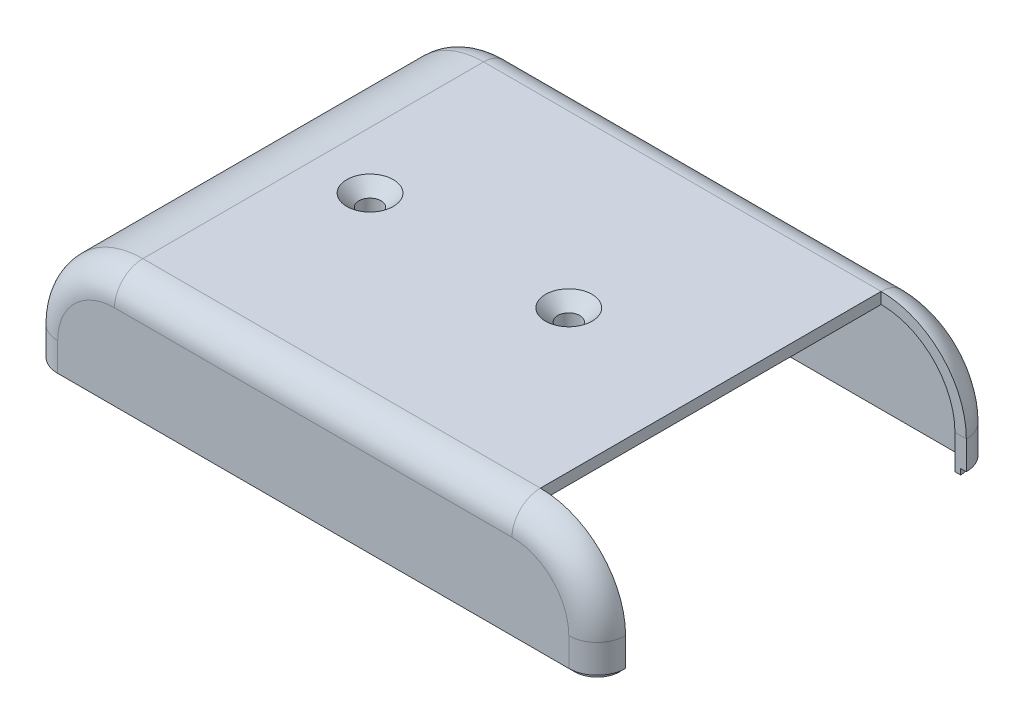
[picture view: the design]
ISO-10303-21;
HEADER;
FILE_DESCRIPTION(('STEP AP214'),'2;1');
FILE_NAME('part.step','',(''),(''),'','','');
FILE_SCHEMA(('AUTOMOTIVE_DESIGN { 1 0 10303 214 1 1 1 1 }'));
ENDSEC;
DATA;
#1=APPLICATION_CONTEXT('core data for automotive mechanical design processes');
#2=APPLICATION_PROTOCOL_DEFINITION('international standard','automotive_design',2000,#1);
#3=PRODUCT_CONTEXT('',#1,'mechanical');
#4=PRODUCT('Part','Part','',(#3));
#5=PRODUCT_RELATED_PRODUCT_CATEGORY('part','',(#4));
#6=PRODUCT_DEFINITION_FORMATION('','',#4);
#7=PRODUCT_DEFINITION_CONTEXT('part definition',#1,'design');
#8=PRODUCT_DEFINITION('design','',#6,#7);
#9=PRODUCT_DEFINITION_SHAPE('','',#8);
#10=(LENGTH_UNIT() NAMED_UNIT(*) SI_UNIT(.MILLI.,.METRE.));
#11=(NAMED_UNIT(*) PLANE_ANGLE_UNIT() SI_UNIT($,.RADIAN.));
#12=(NAMED_UNIT(*) SI_UNIT($,.STERADIAN.) SOLID_ANGLE_UNIT());
#13=UNCERTAINTY_MEASURE_WITH_UNIT(LENGTH_MEASURE(1.E-05),#10,'distance_accuracy_value','');
#14=(GEOMETRIC_REPRESENTATION_CONTEXT(3) GLOBAL_UNCERTAINTY_ASSIGNED_CONTEXT((#13)) GLOBAL_UNIT_ASSIGNED_CONTEXT((#10,
#11,#12)) REPRESENTATION_CONTEXT('',''));
#15=CARTESIAN_POINT('',(0.,0.,0.));
#16=DIRECTION('',(0.,0.,1.));
#17=DIRECTION('',(1.,0.,0.));
#18=AXIS2_PLACEMENT_3D('',#15,#16,#17);
#19=CARTESIAN_POINT('',(50.,18.,-35.));
#20=DIRECTION('',(0.,-1.,0.));
#21=DIRECTION('',(0.,0.,-1.));
#22=AXIS2_PLACEMENT_3D('',#19,#20,#21);
#23=PLANE('',#22);
#24=CARTESIAN_POINT('',(9.99999999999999,18.,0.));
#25=DIRECTION('',(0.,-1.,0.));
#26=DIRECTION('',(0.,0.,-1.));
#27=AXIS2_PLACEMENT_3D('',#24,#25,#26);
#28=CIRCLE('',#27,5.05368379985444);
#29=CARTESIAN_POINT('',(9.99999999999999,18.,-5.05368379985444));
#30=VERTEX_POINT('',#29);
#31=EDGE_CURVE('E44',#30,#30,#28,.F.);
#32=ORIENTED_EDGE('',*,*,#31,.T.);
#33=EDGE_LOOP('',(#32));
#34=FACE_BOUND('',#33,.T.);
#35=CARTESIAN_POINT('',(-25.,18.,0.));
#36=DIRECTION('',(0.,-1.,0.));
#37=DIRECTION('',(0.,0.,-1.));
#38=AXIS2_PLACEMENT_3D('',#35,#36,#37);
#39=CIRCLE('',#38,5.05368379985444);
#40=CARTESIAN_POINT('',(-25.,18.,-5.05368379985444));
#41=VERTEX_POINT('',#40);
#42=EDGE_CURVE('E550',#41,#41,#39,.F.);
#43=ORIENTED_EDGE('',*,*,#42,.T.);
#44=EDGE_LOOP('',(#43));
#45=FACE_BOUND('',#44,.T.);
#46=DIRECTION('',(0.,0.,1.));
#47=VECTOR('',#46,1.);
#48=CARTESIAN_POINT('',(35.,18.,-35.));
#49=LINE('',#48,#47);
#50=CARTESIAN_POINT('',(35.,18.,30.));
#51=VERTEX_POINT('',#50);
#52=CARTESIAN_POINT('',(35.,18.,-30.));
#53=VERTEX_POINT('',#52);
#54=EDGE_CURVE('E435',#51,#53,#49,.F.);
#55=ORIENTED_EDGE('',*,*,#54,.F.);
#56=DIRECTION('',(1.,0.,0.));
#57=VECTOR('',#56,1.);
#58=CARTESIAN_POINT('',(50.,18.,30.));
#59=LINE('',#58,#57);
#60=CARTESIAN_POINT('',(-35.,18.,30.));
#61=VERTEX_POINT('',#60);
#62=EDGE_CURVE('E400',#61,#51,#59,.T.);
#63=ORIENTED_EDGE('',*,*,#62,.F.);
#64=DIRECTION('',(0.,0.,-1.));
#65=VECTOR('',#64,1.);
#66=CARTESIAN_POINT('',(-35.,18.,-35.));
#67=LINE('',#66,#65);
#68=CARTESIAN_POINT('',(-35.,18.,-30.));
#69=VERTEX_POINT('',#68);
#70=EDGE_CURVE('E387',#69,#61,#67,.F.);
#71=ORIENTED_EDGE('',*,*,#70,.F.);
#72=DIRECTION('',(1.,0.,0.));
#73=VECTOR('',#72,1.);
#74=CARTESIAN_POINT('',(50.,18.,-30.));
#75=LINE('',#74,#73);
#76=EDGE_CURVE('E398',#53,#69,#75,.F.);
#77=ORIENTED_EDGE('',*,*,#76,.F.);
#78=EDGE_LOOP('',(#55,#63,#71,#77));
#79=FACE_BOUND('',#78,.T.);
#80=ADVANCED_FACE('F34',(#34,#45,#79),#23,.T.);
#81=CARTESIAN_POINT('',(-50.,20.,-35.));
#82=DIRECTION('',(0.,0.,1.));
#83=DIRECTION('',(1.,0.,0.));
#84=AXIS2_PLACEMENT_3D('',#81,#82,#83);
#85=PLANE('',#84);
#86=CARTESIAN_POINT('',(35.,5.,-35.));
#87=DIRECTION('',(0.,0.,1.));
#88=DIRECTION('',(1.,0.,0.));
#89=AXIS2_PLACEMENT_3D('',#86,#87,#88);
#90=CIRCLE('',#89,10.);
#91=CARTESIAN_POINT('',(35.,15.,-35.));
#92=VERTEX_POINT('',#91);
#93=CARTESIAN_POINT('',(45.,5.,-35.));
#94=VERTEX_POINT('',#93);
#95=EDGE_CURVE('E473',#92,#94,#90,.F.);
#96=ORIENTED_EDGE('',*,*,#95,.T.);
#97=DIRECTION('',(0.,-1.,0.));
#98=VECTOR('',#97,1.);
#99=CARTESIAN_POINT('',(45.,20.,-35.));
#100=LINE('',#99,#98);
#101=CARTESIAN_POINT('',(45.,0.,-35.));
#102=VERTEX_POINT('',#101);
#103=EDGE_CURVE('E475',#94,#102,#100,.T.);
#104=ORIENTED_EDGE('',*,*,#103,.T.);
#105=DIRECTION('',(-1.,0.,0.));
#106=VECTOR('',#105,1.);
#107=CARTESIAN_POINT('',(-50.,0.,-35.));
#108=LINE('',#107,#106);
#109=CARTESIAN_POINT('',(-45.,0.,-35.));
#110=VERTEX_POINT('',#109);
#111=EDGE_CURVE('E448',#102,#110,#108,.T.);
#112=ORIENTED_EDGE('',*,*,#111,.T.);
#113=DIRECTION('',(0.,-1.,0.));
#114=VECTOR('',#113,1.);
#115=CARTESIAN_POINT('',(-45.,20.,-35.));
#116=LINE('',#115,#114);
#117=CARTESIAN_POINT('',(-45.,5.,-35.));
#118=VERTEX_POINT('',#117);
#119=EDGE_CURVE('E471',#110,#118,#116,.F.);
#120=ORIENTED_EDGE('',*,*,#119,.T.);
#121=CARTESIAN_POINT('',(-35.,5.,-35.));
#122=DIRECTION('',(0.,0.,1.));
#123=DIRECTION('',(1.,0.,0.));
#124=AXIS2_PLACEMENT_3D('',#121,#122,#123);
#125=CIRCLE('',#124,10.);
#126=CARTESIAN_POINT('',(-35.,15.,-35.));
#127=VERTEX_POINT('',#126);
#128=EDGE_CURVE('E469',#118,#127,#125,.F.);
#129=ORIENTED_EDGE('',*,*,#128,.T.);
#130=DIRECTION('',(-1.,0.,0.));
#131=VECTOR('',#130,1.);
#132=CARTESIAN_POINT('',(-50.,15.,-35.));
#133=LINE('',#132,#131);
#134=EDGE_CURVE('E467',#127,#92,#133,.F.);
#135=ORIENTED_EDGE('',*,*,#134,.T.);
#136=EDGE_LOOP('',(#96,#104,#112,#120,#129,#135));
#137=FACE_BOUND('',#136,.T.);
#138=ADVANCED_FACE('F583',(#137),#85,.F.);
#139=CARTESIAN_POINT('',(-50.,20.,35.));
#140=DIRECTION('',(1.,0.,0.));
#141=DIRECTION('',(0.,0.,-1.));
#142=AXIS2_PLACEMENT_3D('',#139,#140,#141);
#143=PLANE('',#142);
#144=DIRECTION('',(0.,0.,1.));
#145=VECTOR('',#144,1.);
#146=CARTESIAN_POINT('',(-50.,5.,35.));
#147=LINE('',#146,#145);
#148=CARTESIAN_POINT('',(-50.,5.,30.));
#149=VERTEX_POINT('',#148);
#150=CARTESIAN_POINT('',(-50.,5.,-30.));
#151=VERTEX_POINT('',#150);
#152=EDGE_CURVE('E464',#149,#151,#147,.F.);
#153=ORIENTED_EDGE('',*,*,#152,.T.);
#154=DIRECTION('',(0.,-1.,0.));
#155=VECTOR('',#154,1.);
#156=CARTESIAN_POINT('',(-50.,20.,-30.));
#157=LINE('',#156,#155);
#158=CARTESIAN_POINT('',(-50.,0.,-30.));
#159=VERTEX_POINT('',#158);
#160=EDGE_CURVE('E499',#151,#159,#157,.T.);
#161=ORIENTED_EDGE('',*,*,#160,.T.);
#162=DIRECTION('',(0.,0.,1.));
#163=VECTOR('',#162,1.);
#164=CARTESIAN_POINT('',(-50.,0.,35.));
#165=LINE('',#164,#163);
#166=CARTESIAN_POINT('',(-50.,0.,30.));
#167=VERTEX_POINT('',#166);
#168=EDGE_CURVE('E451',#159,#167,#165,.T.);
#169=ORIENTED_EDGE('',*,*,#168,.T.);
#170=DIRECTION('',(0.,-1.,0.));
#171=VECTOR('',#170,1.);
#172=CARTESIAN_POINT('',(-50.,20.,30.));
#173=LINE('',#172,#171);
#174=EDGE_CURVE('E497',#167,#149,#173,.F.);
#175=ORIENTED_EDGE('',*,*,#174,.T.);
#176=EDGE_LOOP('',(#153,#161,#169,#175));
#177=FACE_BOUND('',#176,.T.);
#178=ADVANCED_FACE('F588',(#177),#143,.F.);
#179=CARTESIAN_POINT('',(-50.,20.,35.));
#180=DIRECTION('',(0.,0.,-1.));
#181=DIRECTION('',(-1.,0.,0.));
#182=AXIS2_PLACEMENT_3D('',#179,#180,#181);
#183=PLANE('',#182);
#184=CARTESIAN_POINT('',(-35.,5.,35.));
#185=DIRECTION('',(0.,0.,-1.));
#186=DIRECTION('',(-1.,0.,0.));
#187=AXIS2_PLACEMENT_3D('',#184,#185,#186);
#188=CIRCLE('',#187,10.);
#189=CARTESIAN_POINT('',(-35.,15.,35.));
#190=VERTEX_POINT('',#189);
#191=CARTESIAN_POINT('',(-45.,5.,35.));
#192=VERTEX_POINT('',#191);
#193=EDGE_CURVE('E511',#190,#192,#188,.F.);
#194=ORIENTED_EDGE('',*,*,#193,.T.);
#195=DIRECTION('',(0.,-1.,0.));
#196=VECTOR('',#195,1.);
#197=CARTESIAN_POINT('',(-45.,20.,35.));
#198=LINE('',#197,#196);
#199=CARTESIAN_POINT('',(-45.,0.,35.));
#200=VERTEX_POINT('',#199);
#201=EDGE_CURVE('E513',#192,#200,#198,.T.);
#202=ORIENTED_EDGE('',*,*,#201,.T.);
#203=DIRECTION('',(1.,0.,0.));
#204=VECTOR('',#203,1.);
#205=CARTESIAN_POINT('',(-50.,0.,35.));
#206=LINE('',#205,#204);
#207=CARTESIAN_POINT('',(45.,0.,35.));
#208=VERTEX_POINT('',#207);
#209=EDGE_CURVE('E455',#200,#208,#206,.T.);
#210=ORIENTED_EDGE('',*,*,#209,.T.);
#211=DIRECTION('',(0.,-1.,0.));
#212=VECTOR('',#211,1.);
#213=CARTESIAN_POINT('',(45.,20.,35.));
#214=LINE('',#213,#212);
#215=CARTESIAN_POINT('',(45.,5.,35.));
#216=VERTEX_POINT('',#215);
#217=EDGE_CURVE('E509',#208,#216,#214,.F.);
#218=ORIENTED_EDGE('',*,*,#217,.T.);
#219=CARTESIAN_POINT('',(35.,5.,35.));
#220=DIRECTION('',(0.,0.,-1.));
#221=DIRECTION('',(-1.,0.,0.));
#222=AXIS2_PLACEMENT_3D('',#219,#220,#221);
#223=CIRCLE('',#222,10.);
#224=CARTESIAN_POINT('',(35.,15.,35.));
#225=VERTEX_POINT('',#224);
#226=EDGE_CURVE('E507',#216,#225,#223,.F.);
#227=ORIENTED_EDGE('',*,*,#226,.T.);
#228=DIRECTION('',(1.,0.,0.));
#229=VECTOR('',#228,1.);
#230=CARTESIAN_POINT('',(-50.,15.,35.));
#231=LINE('',#230,#229);
#232=EDGE_CURVE('E505',#225,#190,#231,.F.);
#233=ORIENTED_EDGE('',*,*,#232,.T.);
#234=EDGE_LOOP('',(#194,#202,#210,#218,#227,#233));
#235=FACE_BOUND('',#234,.T.);
#236=ADVANCED_FACE('F638',(#235),#183,.F.);
#237=CARTESIAN_POINT('',(50.,20.,-35.));
#238=DIRECTION('',(0.,-1.,0.));
#239=DIRECTION('',(0.,0.,-1.));
#240=AXIS2_PLACEMENT_3D('',#237,#238,#239);
#241=PLANE('',#240);
#242=CARTESIAN_POINT('',(9.99999999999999,20.,0.));
#243=DIRECTION('',(0.,1.,0.));
#244=DIRECTION('',(0.,0.,1.));
#245=AXIS2_PLACEMENT_3D('',#242,#243,#244);
#246=CIRCLE('',#245,4.1);
#247=CARTESIAN_POINT('',(9.99999999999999,20.,4.1));
#248=VERTEX_POINT('',#247);
#249=EDGE_CURVE('E260',#248,#248,#246,.T.);
#250=ORIENTED_EDGE('',*,*,#249,.F.);
#251=EDGE_LOOP('',(#250));
#252=FACE_BOUND('',#251,.T.);
#253=CARTESIAN_POINT('',(-25.,20.,0.));
#254=DIRECTION('',(0.,1.,0.));
#255=DIRECTION('',(0.,0.,1.));
#256=AXIS2_PLACEMENT_3D('',#253,#254,#255);
#257=CIRCLE('',#256,4.1);
#258=CARTESIAN_POINT('',(-25.,20.,4.1));
#259=VERTEX_POINT('',#258);
#260=EDGE_CURVE('E339',#259,#259,#257,.T.);
#261=ORIENTED_EDGE('',*,*,#260,.F.);
#262=EDGE_LOOP('',(#261));
#263=FACE_BOUND('',#262,.T.);
#264=DIRECTION('',(0.,0.,-1.));
#265=VECTOR('',#264,1.);
#266=CARTESIAN_POINT('',(35.,20.,-35.));
#267=LINE('',#266,#265);
#268=CARTESIAN_POINT('',(35.,20.,30.));
#269=VERTEX_POINT('',#268);
#270=CARTESIAN_POINT('',(35.,20.,-30.));
#271=VERTEX_POINT('',#270);
#272=EDGE_CURVE('E461',#269,#271,#267,.T.);
#273=ORIENTED_EDGE('',*,*,#272,.T.);
#274=DIRECTION('',(-1.,0.,0.));
#275=VECTOR('',#274,1.);
#276=CARTESIAN_POINT('',(50.,20.,-30.));
#277=LINE('',#276,#275);
#278=CARTESIAN_POINT('',(-35.,20.,-30.));
#279=VERTEX_POINT('',#278);
#280=EDGE_CURVE('E519',#271,#279,#277,.T.);
#281=ORIENTED_EDGE('',*,*,#280,.T.);
#282=DIRECTION('',(0.,0.,1.));
#283=VECTOR('',#282,1.);
#284=CARTESIAN_POINT('',(-35.,20.,-35.));
#285=LINE('',#284,#283);
#286=CARTESIAN_POINT('',(-35.,20.,30.));
#287=VERTEX_POINT('',#286);
#288=EDGE_CURVE('E458',#279,#287,#285,.T.);
#289=ORIENTED_EDGE('',*,*,#288,.T.);
#290=DIRECTION('',(1.,0.,0.));
#291=VECTOR('',#290,1.);
#292=CARTESIAN_POINT('',(50.,20.,30.));
#293=LINE('',#292,#291);
#294=EDGE_CURVE('E516',#287,#269,#293,.T.);
#295=ORIENTED_EDGE('',*,*,#294,.T.);
#296=EDGE_LOOP('',(#273,#281,#289,#295));
#297=FACE_BOUND('',#296,.T.);
#298=ADVANCED_FACE('F634',(#252,#263,#297),#241,.F.);
#299=CARTESIAN_POINT('',(50.,0.,-35.));
#300=DIRECTION('',(0.,-1.,0.));
#301=DIRECTION('',(0.,0.,-1.));
#302=AXIS2_PLACEMENT_3D('',#299,#300,#301);
#303=PLANE('',#302);
#304=CARTESIAN_POINT('',(45.,0.,-30.));
#305=DIRECTION('',(0.,-1.,0.));
#306=DIRECTION('',(1.,0.,0.));
#307=AXIS2_PLACEMENT_3D('',#304,#305,#306);
#308=CIRCLE('',#307,4.);
#309=CARTESIAN_POINT('',(45.,0.,-34.));
#310=VERTEX_POINT('',#309);
#311=CARTESIAN_POINT('',(49.,0.,-30.));
#312=VERTEX_POINT('',#311);
#313=EDGE_CURVE('E38',#310,#312,#308,.T.);
#314=ORIENTED_EDGE('',*,*,#313,.F.);
#315=DIRECTION('',(1.,0.,0.));
#316=VECTOR('',#315,1.);
#317=CARTESIAN_POINT('',(45.,0.,-34.));
#318=LINE('',#317,#316);
#319=CARTESIAN_POINT('',(-45.,0.,-34.));
#320=VERTEX_POINT('',#319);
#321=EDGE_CURVE('E55',#320,#310,#318,.T.);
#322=ORIENTED_EDGE('',*,*,#321,.F.);
#323=CARTESIAN_POINT('',(-45.,0.,-30.));
#324=DIRECTION('',(0.,-1.,0.));
#325=DIRECTION('',(1.,0.,0.));
#326=AXIS2_PLACEMENT_3D('',#323,#324,#325);
#327=CIRCLE('',#326,4.);
#328=CARTESIAN_POINT('',(-49.,0.,-30.));
#329=VERTEX_POINT('',#328);
#330=EDGE_CURVE('E314',#329,#320,#327,.T.);
#331=ORIENTED_EDGE('',*,*,#330,.F.);
#332=DIRECTION('',(0.,0.,1.));
#333=VECTOR('',#332,1.);
#334=CARTESIAN_POINT('',(-49.,0.,-30.));
#335=LINE('',#334,#333);
#336=CARTESIAN_POINT('',(-49.,0.,30.));
#337=VERTEX_POINT('',#336);
#338=EDGE_CURVE('E311',#337,#329,#335,.F.);
#339=ORIENTED_EDGE('',*,*,#338,.F.);
#340=CARTESIAN_POINT('',(-45.,0.,30.));
#341=DIRECTION('',(0.,-1.,0.));
#342=DIRECTION('',(1.,0.,0.));
#343=AXIS2_PLACEMENT_3D('',#340,#341,#342);
#344=CIRCLE('',#343,4.);
#345=CARTESIAN_POINT('',(-45.,0.,34.));
#346=VERTEX_POINT('',#345);
#347=EDGE_CURVE('E307',#346,#337,#344,.T.);
#348=ORIENTED_EDGE('',*,*,#347,.F.);
#349=DIRECTION('',(1.,0.,0.));
#350=VECTOR('',#349,1.);
#351=CARTESIAN_POINT('',(-45.,0.,34.));
#352=LINE('',#351,#350);
#353=CARTESIAN_POINT('',(45.,0.,34.));
#354=VERTEX_POINT('',#353);
#355=EDGE_CURVE('E304',#354,#346,#352,.F.);
#356=ORIENTED_EDGE('',*,*,#355,.F.);
#357=CARTESIAN_POINT('',(45.,0.,30.));
#358=DIRECTION('',(0.,-1.,0.));
#359=DIRECTION('',(1.,0.,0.));
#360=AXIS2_PLACEMENT_3D('',#357,#358,#359);
#361=CIRCLE('',#360,4.);
#362=CARTESIAN_POINT('',(49.,0.,30.));
#363=VERTEX_POINT('',#362);
#364=EDGE_CURVE('E308',#363,#354,#361,.T.);
#365=ORIENTED_EDGE('',*,*,#364,.F.);
#366=DIRECTION('',(1.,0.,0.));
#367=VECTOR('',#366,1.);
#368=CARTESIAN_POINT('',(50.,0.,30.));
#369=LINE('',#368,#367);
#370=CARTESIAN_POINT('',(50.,0.,30.));
#371=VERTEX_POINT('',#370);
#372=EDGE_CURVE('E360',#363,#371,#369,.T.);
#373=ORIENTED_EDGE('',*,*,#372,.T.);
#374=CARTESIAN_POINT('',(45.,0.,30.));
#375=DIRECTION('',(0.,-1.,0.));
#376=DIRECTION('',(0.,0.,-1.));
#377=AXIS2_PLACEMENT_3D('',#374,#375,#376);
#378=CIRCLE('',#377,5.);
#379=EDGE_CURVE('E478',#371,#208,#378,.T.);
#380=ORIENTED_EDGE('',*,*,#379,.T.);
#381=ORIENTED_EDGE('',*,*,#209,.F.);
#382=CARTESIAN_POINT('',(-45.,0.,30.));
#383=DIRECTION('',(0.,-1.,0.));
#384=DIRECTION('',(0.,0.,-1.));
#385=AXIS2_PLACEMENT_3D('',#382,#383,#384);
#386=CIRCLE('',#385,5.);
#387=EDGE_CURVE('E480',#200,#167,#386,.T.);
#388=ORIENTED_EDGE('',*,*,#387,.T.);
#389=ORIENTED_EDGE('',*,*,#168,.F.);
#390=CARTESIAN_POINT('',(-45.,0.,-30.));
#391=DIRECTION('',(0.,-1.,0.));
#392=DIRECTION('',(0.,0.,-1.));
#393=AXIS2_PLACEMENT_3D('',#390,#391,#392);
#394=CIRCLE('',#393,5.);
#395=EDGE_CURVE('E482',#159,#110,#394,.T.);
#396=ORIENTED_EDGE('',*,*,#395,.T.);
#397=ORIENTED_EDGE('',*,*,#111,.F.);
#398=CARTESIAN_POINT('',(45.,0.,-30.));
#399=DIRECTION('',(0.,-1.,0.));
#400=DIRECTION('',(0.,0.,-1.));
#401=AXIS2_PLACEMENT_3D('',#398,#399,#400);
#402=CIRCLE('',#401,5.);
#403=CARTESIAN_POINT('',(50.,0.,-30.));
#404=VERTEX_POINT('',#403);
#405=EDGE_CURVE('E484',#102,#404,#402,.T.);
#406=ORIENTED_EDGE('',*,*,#405,.T.);
#407=DIRECTION('',(1.,0.,0.));
#408=VECTOR('',#407,1.);
#409=CARTESIAN_POINT('',(50.,0.,-30.));
#410=LINE('',#409,#408);
#411=EDGE_CURVE('E358',#312,#404,#410,.T.);
#412=ORIENTED_EDGE('',*,*,#411,.F.);
#413=EDGE_LOOP('',(#314,#322,#331,#339,#348,#356,#365,#373,#380,#381,#388,#389,#396,#397,#406,#412));
#414=FACE_BOUND('',#413,.T.);
#415=ADVANCED_FACE('F637',(#414),#303,.T.);
#416=CARTESIAN_POINT('',(-35.,5.,-35.));
#417=DIRECTION('',(0.,0.,1.));
#418=DIRECTION('',(1.,0.,0.));
#419=AXIS2_PLACEMENT_3D('',#416,#417,#418);
#420=CYLINDRICAL_SURFACE('',#419,15.);
#421=ORIENTED_EDGE('',*,*,#288,.F.);
#422=CARTESIAN_POINT('',(-35.,5.,-30.));
#423=DIRECTION('',(0.,0.,1.));
#424=DIRECTION('',(1.,0.,0.));
#425=AXIS2_PLACEMENT_3D('',#422,#423,#424);
#426=CIRCLE('',#425,15.);
#427=EDGE_CURVE('E503',#279,#151,#426,.T.);
#428=ORIENTED_EDGE('',*,*,#427,.T.);
#429=ORIENTED_EDGE('',*,*,#152,.F.);
#430=CARTESIAN_POINT('',(-35.,5.,30.));
#431=DIRECTION('',(0.,0.,-1.));
#432=DIRECTION('',(-1.,0.,0.));
#433=AXIS2_PLACEMENT_3D('',#430,#431,#432);
#434=CIRCLE('',#433,15.);
#435=EDGE_CURVE('E501',#149,#287,#434,.T.);
#436=ORIENTED_EDGE('',*,*,#435,.T.);
#437=EDGE_LOOP('',(#421,#428,#429,#436));
#438=FACE_BOUND('',#437,.T.);
#439=ADVANCED_FACE('F642',(#438),#420,.T.);
#440=CARTESIAN_POINT('',(-45.,20.,-30.));
#441=DIRECTION('',(0.,-1.,0.));
#442=DIRECTION('',(0.,0.,-1.));
#443=AXIS2_PLACEMENT_3D('',#440,#441,#442);
#444=CYLINDRICAL_SURFACE('',#443,5.);
#445=ORIENTED_EDGE('',*,*,#395,.F.);
#446=ORIENTED_EDGE('',*,*,#160,.F.);
#447=CARTESIAN_POINT('',(-45.,5.,-30.));
#448=DIRECTION('',(0.,1.,0.));
#449=DIRECTION('',(0.,0.,1.));
#450=AXIS2_PLACEMENT_3D('',#447,#448,#449);
#451=CIRCLE('',#450,5.);
#452=EDGE_CURVE('E452',#118,#151,#451,.T.);
#453=ORIENTED_EDGE('',*,*,#452,.F.);
#454=ORIENTED_EDGE('',*,*,#119,.F.);
#455=EDGE_LOOP('',(#445,#446,#453,#454));
#456=FACE_BOUND('',#455,.T.);
#457=ADVANCED_FACE('F651',(#456),#444,.T.);
#458=CARTESIAN_POINT('',(-35.,5.,-30.));
#459=DIRECTION('',(0.,0.,1.));
#460=DIRECTION('',(1.,0.,0.));
#461=AXIS2_PLACEMENT_3D('',#458,#459,#460);
#462=TOROIDAL_SURFACE('',#461,10.,5.);
#463=ORIENTED_EDGE('',*,*,#452,.T.);
#464=ORIENTED_EDGE('',*,*,#427,.F.);
#465=CARTESIAN_POINT('',(-35.,15.,-30.));
#466=DIRECTION('',(1.,0.,0.));
#467=DIRECTION('',(0.,0.,-1.));
#468=AXIS2_PLACEMENT_3D('',#465,#466,#467);
#469=CIRCLE('',#468,5.);
#470=EDGE_CURVE('E529',#127,#279,#469,.T.);
#471=ORIENTED_EDGE('',*,*,#470,.F.);
#472=ORIENTED_EDGE('',*,*,#128,.F.);
#473=EDGE_LOOP('',(#463,#464,#471,#472));
#474=FACE_BOUND('',#473,.T.);
#475=ADVANCED_FACE('F665',(#474),#462,.T.);
#476=CARTESIAN_POINT('',(50.,15.,-30.));
#477=DIRECTION('',(-1.,0.,0.));
#478=DIRECTION('',(0.,0.,1.));
#479=AXIS2_PLACEMENT_3D('',#476,#477,#478);
#480=CYLINDRICAL_SURFACE('',#479,5.);
#481=ORIENTED_EDGE('',*,*,#470,.T.);
#482=ORIENTED_EDGE('',*,*,#280,.F.);
#483=CARTESIAN_POINT('',(35.,15.,-30.));
#484=DIRECTION('',(1.,0.,0.));
#485=DIRECTION('',(0.,0.,-1.));
#486=AXIS2_PLACEMENT_3D('',#483,#484,#485);
#487=CIRCLE('',#486,5.);
#488=EDGE_CURVE('E525',#92,#271,#487,.T.);
#489=ORIENTED_EDGE('',*,*,#488,.F.);
#490=ORIENTED_EDGE('',*,*,#134,.F.);
#491=EDGE_LOOP('',(#481,#482,#489,#490));
#492=FACE_BOUND('',#491,.T.);
#493=ADVANCED_FACE('F661',(#492),#480,.T.);
#494=CARTESIAN_POINT('',(35.,5.,-30.));
#495=DIRECTION('',(0.,0.,1.));
#496=DIRECTION('',(1.,0.,0.));
#497=AXIS2_PLACEMENT_3D('',#494,#495,#496);
#498=TOROIDAL_SURFACE('',#497,10.,5.);
#499=ORIENTED_EDGE('',*,*,#488,.T.);
#500=CARTESIAN_POINT('',(35.,5.,-30.));
#501=DIRECTION('',(0.,0.,1.));
#502=DIRECTION('',(1.,0.,0.));
#503=AXIS2_PLACEMENT_3D('',#500,#501,#502);
#504=CIRCLE('',#503,15.);
#505=CARTESIAN_POINT('',(50.,5.,-30.));
#506=VERTEX_POINT('',#505);
#507=EDGE_CURVE('E494',#506,#271,#504,.T.);
#508=ORIENTED_EDGE('',*,*,#507,.F.);
#509=CARTESIAN_POINT('',(45.,5.,-30.));
#510=DIRECTION('',(0.,-1.,0.));
#511=DIRECTION('',(0.,0.,-1.));
#512=AXIS2_PLACEMENT_3D('',#509,#510,#511);
#513=CIRCLE('',#512,5.);
#514=EDGE_CURVE('E522',#94,#506,#513,.T.);
#515=ORIENTED_EDGE('',*,*,#514,.F.);
#516=ORIENTED_EDGE('',*,*,#95,.F.);
#517=EDGE_LOOP('',(#499,#508,#515,#516));
#518=FACE_BOUND('',#517,.T.);
#519=ADVANCED_FACE('F657',(#518),#498,.T.);
#520=CARTESIAN_POINT('',(45.,20.,-30.));
#521=DIRECTION('',(0.,-1.,0.));
#522=DIRECTION('',(0.,0.,-1.));
#523=AXIS2_PLACEMENT_3D('',#520,#521,#522);
#524=CYLINDRICAL_SURFACE('',#523,5.);
#525=ORIENTED_EDGE('',*,*,#514,.T.);
#526=DIRECTION('',(0.,-1.,0.));
#527=VECTOR('',#526,1.);
#528=CARTESIAN_POINT('',(50.,20.,-30.));
#529=LINE('',#528,#527);
#530=EDGE_CURVE('E490',#404,#506,#529,.F.);
#531=ORIENTED_EDGE('',*,*,#530,.F.);
#532=ORIENTED_EDGE('',*,*,#405,.F.);
#533=ORIENTED_EDGE('',*,*,#103,.F.);
#534=EDGE_LOOP('',(#525,#531,#532,#533));
#535=FACE_BOUND('',#534,.T.);
#536=ADVANCED_FACE('F653',(#535),#524,.T.);
#537=CARTESIAN_POINT('',(45.,20.,30.));
#538=DIRECTION('',(0.,-1.,0.));
#539=DIRECTION('',(0.,0.,-1.));
#540=AXIS2_PLACEMENT_3D('',#537,#538,#539);
#541=CYLINDRICAL_SURFACE('',#540,5.);
#542=ORIENTED_EDGE('',*,*,#379,.F.);
#543=DIRECTION('',(0.,-1.,0.));
#544=VECTOR('',#543,1.);
#545=CARTESIAN_POINT('',(50.,20.,30.));
#546=LINE('',#545,#544);
#547=CARTESIAN_POINT('',(50.,5.,30.));
#548=VERTEX_POINT('',#547);
#549=EDGE_CURVE('E487',#548,#371,#546,.T.);
#550=ORIENTED_EDGE('',*,*,#549,.F.);
#551=CARTESIAN_POINT('',(45.,5.,30.));
#552=DIRECTION('',(0.,1.,0.));
#553=DIRECTION('',(0.,0.,1.));
#554=AXIS2_PLACEMENT_3D('',#551,#552,#553);
#555=CIRCLE('',#554,5.);
#556=EDGE_CURVE('E526',#216,#548,#555,.T.);
#557=ORIENTED_EDGE('',*,*,#556,.F.);
#558=ORIENTED_EDGE('',*,*,#217,.F.);
#559=EDGE_LOOP('',(#542,#550,#557,#558));
#560=FACE_BOUND('',#559,.T.);
#561=ADVANCED_FACE('F656',(#560),#541,.T.);
#562=CARTESIAN_POINT('',(35.,5.,30.));
#563=DIRECTION('',(0.,0.,-1.));
#564=DIRECTION('',(-1.,0.,0.));
#565=AXIS2_PLACEMENT_3D('',#562,#563,#564);
#566=TOROIDAL_SURFACE('',#565,10.,5.);
#567=ORIENTED_EDGE('',*,*,#556,.T.);
#568=CARTESIAN_POINT('',(35.,5.,30.));
#569=DIRECTION('',(0.,0.,-1.));
#570=DIRECTION('',(-1.,0.,0.));
#571=AXIS2_PLACEMENT_3D('',#568,#569,#570);
#572=CIRCLE('',#571,15.);
#573=EDGE_CURVE('E492',#269,#548,#572,.T.);
#574=ORIENTED_EDGE('',*,*,#573,.F.);
#575=CARTESIAN_POINT('',(35.,15.,30.));
#576=DIRECTION('',(-1.,0.,0.));
#577=DIRECTION('',(0.,0.,1.));
#578=AXIS2_PLACEMENT_3D('',#575,#576,#577);
#579=CIRCLE('',#578,5.);
#580=EDGE_CURVE('E539',#225,#269,#579,.T.);
#581=ORIENTED_EDGE('',*,*,#580,.F.);
#582=ORIENTED_EDGE('',*,*,#226,.F.);
#583=EDGE_LOOP('',(#567,#574,#581,#582));
#584=FACE_BOUND('',#583,.T.);
#585=ADVANCED_FACE('F685',(#584),#566,.T.);
#586=CARTESIAN_POINT('',(50.,15.,30.));
#587=DIRECTION('',(1.,0.,0.));
#588=DIRECTION('',(0.,0.,-1.));
#589=AXIS2_PLACEMENT_3D('',#586,#587,#588);
#590=CYLINDRICAL_SURFACE('',#589,5.);
#591=ORIENTED_EDGE('',*,*,#580,.T.);
#592=ORIENTED_EDGE('',*,*,#294,.F.);
#593=CARTESIAN_POINT('',(-35.,15.,30.));
#594=DIRECTION('',(-1.,0.,0.));
#595=DIRECTION('',(0.,0.,1.));
#596=AXIS2_PLACEMENT_3D('',#593,#594,#595);
#597=CIRCLE('',#596,5.);
#598=EDGE_CURVE('E536',#190,#287,#597,.T.);
#599=ORIENTED_EDGE('',*,*,#598,.F.);
#600=ORIENTED_EDGE('',*,*,#232,.F.);
#601=EDGE_LOOP('',(#591,#592,#599,#600));
#602=FACE_BOUND('',#601,.T.);
#603=ADVANCED_FACE('F681',(#602),#590,.T.);
#604=CARTESIAN_POINT('',(-35.,5.,30.));
#605=DIRECTION('',(0.,0.,-1.));
#606=DIRECTION('',(-1.,0.,0.));
#607=AXIS2_PLACEMENT_3D('',#604,#605,#606);
#608=TOROIDAL_SURFACE('',#607,10.,5.);
#609=ORIENTED_EDGE('',*,*,#598,.T.);
#610=ORIENTED_EDGE('',*,*,#435,.F.);
#611=CARTESIAN_POINT('',(-45.,5.,30.));
#612=DIRECTION('',(0.,-1.,0.));
#613=DIRECTION('',(0.,0.,-1.));
#614=AXIS2_PLACEMENT_3D('',#611,#612,#613);
#615=CIRCLE('',#614,5.);
#616=EDGE_CURVE('E447',#192,#149,#615,.T.);
#617=ORIENTED_EDGE('',*,*,#616,.F.);
#618=ORIENTED_EDGE('',*,*,#193,.F.);
#619=EDGE_LOOP('',(#609,#610,#617,#618));
#620=FACE_BOUND('',#619,.T.);
#621=ADVANCED_FACE('F677',(#620),#608,.T.);
#622=CARTESIAN_POINT('',(-45.,20.,30.));
#623=DIRECTION('',(0.,-1.,0.));
#624=DIRECTION('',(0.,0.,-1.));
#625=AXIS2_PLACEMENT_3D('',#622,#623,#624);
#626=CYLINDRICAL_SURFACE('',#625,5.);
#627=ORIENTED_EDGE('',*,*,#616,.T.);
#628=ORIENTED_EDGE('',*,*,#174,.F.);
#629=ORIENTED_EDGE('',*,*,#387,.F.);
#630=ORIENTED_EDGE('',*,*,#201,.F.);
#631=EDGE_LOOP('',(#627,#628,#629,#630));
#632=FACE_BOUND('',#631,.T.);
#633=ADVANCED_FACE('F673',(#632),#626,.T.);
#634=CARTESIAN_POINT('',(35.,5.,30.));
#635=DIRECTION('',(0.,0.,1.));
#636=DIRECTION('',(1.,0.,0.));
#637=AXIS2_PLACEMENT_3D('',#634,#635,#636);
#638=PLANE('',#637);
#639=ORIENTED_EDGE('',*,*,#573,.T.);
#640=DIRECTION('',(1.,0.,0.));
#641=VECTOR('',#640,1.);
#642=CARTESIAN_POINT('',(50.,5.,30.));
#643=LINE('',#642,#641);
#644=CARTESIAN_POINT('',(48.,5.,30.));
#645=VERTEX_POINT('',#644);
#646=EDGE_CURVE('E365',#645,#548,#643,.T.);
#647=ORIENTED_EDGE('',*,*,#646,.F.);
#648=CARTESIAN_POINT('',(35.,5.,30.));
#649=DIRECTION('',(0.,0.,1.));
#650=DIRECTION('',(1.,0.,0.));
#651=AXIS2_PLACEMENT_3D('',#648,#649,#650);
#652=CIRCLE('',#651,13.);
#653=EDGE_CURVE('E361',#51,#645,#652,.F.);
#654=ORIENTED_EDGE('',*,*,#653,.F.);
#655=DIRECTION('',(0.,1.,0.));
#656=VECTOR('',#655,1.);
#657=CARTESIAN_POINT('',(35.,5.,30.));
#658=LINE('',#657,#656);
#659=EDGE_CURVE('E444',#269,#51,#658,.F.);
#660=ORIENTED_EDGE('',*,*,#659,.F.);
#661=EDGE_LOOP('',(#639,#647,#654,#660));
#662=FACE_BOUND('',#661,.T.);
#663=ADVANCED_FACE('F676',(#662),#638,.F.);
#664=CARTESIAN_POINT('',(35.,20.,0.));
#665=DIRECTION('',(1.,0.,0.));
#666=DIRECTION('',(0.,0.,-1.));
#667=AXIS2_PLACEMENT_3D('',#664,#665,#666);
#668=PLANE('',#667);
#669=ORIENTED_EDGE('',*,*,#272,.F.);
#670=ORIENTED_EDGE('',*,*,#659,.T.);
#671=ORIENTED_EDGE('',*,*,#54,.T.);
#672=DIRECTION('',(0.,1.,0.));
#673=VECTOR('',#672,1.);
#674=CARTESIAN_POINT('',(35.,20.,-30.));
#675=LINE('',#674,#673);
#676=EDGE_CURVE('E441',#271,#53,#675,.F.);
#677=ORIENTED_EDGE('',*,*,#676,.F.);
#678=EDGE_LOOP('',(#669,#670,#671,#677));
#679=FACE_BOUND('',#678,.T.);
#680=ADVANCED_FACE('F761',(#679),#668,.T.);
#681=CARTESIAN_POINT('',(35.,5.,-30.));
#682=DIRECTION('',(0.,0.,-1.));
#683=DIRECTION('',(-1.,0.,0.));
#684=AXIS2_PLACEMENT_3D('',#681,#682,#683);
#685=PLANE('',#684);
#686=ORIENTED_EDGE('',*,*,#507,.T.);
#687=ORIENTED_EDGE('',*,*,#676,.T.);
#688=CARTESIAN_POINT('',(35.,5.,-30.));
#689=DIRECTION('',(0.,0.,-1.));
#690=DIRECTION('',(-1.,0.,0.));
#691=AXIS2_PLACEMENT_3D('',#688,#689,#690);
#692=CIRCLE('',#691,13.);
#693=CARTESIAN_POINT('',(48.,5.,-30.));
#694=VERTEX_POINT('',#693);
#695=EDGE_CURVE('E432',#694,#53,#692,.F.);
#696=ORIENTED_EDGE('',*,*,#695,.F.);
#697=DIRECTION('',(1.,0.,0.));
#698=VECTOR('',#697,1.);
#699=CARTESIAN_POINT('',(50.,5.,-30.));
#700=LINE('',#699,#698);
#701=EDGE_CURVE('E355',#694,#506,#700,.T.);
#702=ORIENTED_EDGE('',*,*,#701,.T.);
#703=EDGE_LOOP('',(#686,#687,#696,#702));
#704=FACE_BOUND('',#703,.T.);
#705=ADVANCED_FACE('F723',(#704),#685,.F.);
#706=CARTESIAN_POINT('',(50.,20.,30.));
#707=DIRECTION('',(0.,0.,-1.));
#708=DIRECTION('',(0.,-1.,0.));
#709=AXIS2_PLACEMENT_3D('',#706,#707,#708);
#710=PLANE('',#709);
#711=ORIENTED_EDGE('',*,*,#549,.T.);
#712=ORIENTED_EDGE('',*,*,#372,.F.);
#713=DIRECTION('',(0.,1.,0.));
#714=VECTOR('',#713,1.);
#715=CARTESIAN_POINT('',(49.,-1.,30.));
#716=LINE('',#715,#714);
#717=CARTESIAN_POINT('',(49.,-1.,30.));
#718=VERTEX_POINT('',#717);
#719=EDGE_CURVE('E261',#718,#363,#716,.T.);
#720=ORIENTED_EDGE('',*,*,#719,.F.);
#721=DIRECTION('',(-1.,0.,0.));
#722=VECTOR('',#721,1.);
#723=CARTESIAN_POINT('',(49.,-1.,30.));
#724=LINE('',#723,#722);
#725=CARTESIAN_POINT('',(48.,-1.,30.));
#726=VERTEX_POINT('',#725);
#727=EDGE_CURVE('E288',#718,#726,#724,.T.);
#728=ORIENTED_EDGE('',*,*,#727,.T.);
#729=DIRECTION('',(0.,-1.,0.));
#730=VECTOR('',#729,1.);
#731=CARTESIAN_POINT('',(48.,20.,30.));
#732=LINE('',#731,#730);
#733=EDGE_CURVE('E431',#645,#726,#732,.T.);
#734=ORIENTED_EDGE('',*,*,#733,.F.);
#735=ORIENTED_EDGE('',*,*,#646,.T.);
#736=EDGE_LOOP('',(#711,#712,#720,#728,#734,#735));
#737=FACE_BOUND('',#736,.T.);
#738=ADVANCED_FACE('F741',(#737),#710,.T.);
#739=CARTESIAN_POINT('',(50.,20.,-30.));
#740=DIRECTION('',(0.,0.,-1.));
#741=DIRECTION('',(0.,-1.,0.));
#742=AXIS2_PLACEMENT_3D('',#739,#740,#741);
#743=PLANE('',#742);
#744=ORIENTED_EDGE('',*,*,#530,.T.);
#745=ORIENTED_EDGE('',*,*,#701,.F.);
#746=DIRECTION('',(0.,-1.,0.));
#747=VECTOR('',#746,1.);
#748=CARTESIAN_POINT('',(48.,20.,-30.));
#749=LINE('',#748,#747);
#750=CARTESIAN_POINT('',(48.,-1.,-30.));
#751=VERTEX_POINT('',#750);
#752=EDGE_CURVE('E265',#751,#694,#749,.F.);
#753=ORIENTED_EDGE('',*,*,#752,.F.);
#754=DIRECTION('',(1.,0.,0.));
#755=VECTOR('',#754,1.);
#756=CARTESIAN_POINT('',(48.,-1.,-30.));
#757=LINE('',#756,#755);
#758=CARTESIAN_POINT('',(49.,-1.,-30.));
#759=VERTEX_POINT('',#758);
#760=EDGE_CURVE('E248',#751,#759,#757,.T.);
#761=ORIENTED_EDGE('',*,*,#760,.T.);
#762=DIRECTION('',(0.,1.,0.));
#763=VECTOR('',#762,1.);
#764=CARTESIAN_POINT('',(49.,-1.,-30.));
#765=LINE('',#764,#763);
#766=EDGE_CURVE('E257',#759,#312,#765,.T.);
#767=ORIENTED_EDGE('',*,*,#766,.T.);
#768=ORIENTED_EDGE('',*,*,#411,.T.);
#769=EDGE_LOOP('',(#744,#745,#753,#761,#767,#768));
#770=FACE_BOUND('',#769,.T.);
#771=ADVANCED_FACE('F263',(#770),#743,.F.);
#772=CARTESIAN_POINT('',(-50.,20.,-33.));
#773=DIRECTION('',(0.,0.,1.));
#774=DIRECTION('',(1.,0.,0.));
#775=AXIS2_PLACEMENT_3D('',#772,#773,#774);
#776=PLANE('',#775);
#777=CARTESIAN_POINT('',(35.,5.,-33.));
#778=DIRECTION('',(0.,0.,1.));
#779=DIRECTION('',(1.,0.,0.));
#780=AXIS2_PLACEMENT_3D('',#777,#778,#779);
#781=CIRCLE('',#780,10.);
#782=CARTESIAN_POINT('',(35.,15.,-33.));
#783=VERTEX_POINT('',#782);
#784=CARTESIAN_POINT('',(45.,5.,-33.));
#785=VERTEX_POINT('',#784);
#786=EDGE_CURVE('E369',#783,#785,#781,.F.);
#787=ORIENTED_EDGE('',*,*,#786,.F.);
#788=DIRECTION('',(1.,0.,0.));
#789=VECTOR('',#788,1.);
#790=CARTESIAN_POINT('',(-50.,15.,-33.));
#791=LINE('',#790,#789);
#792=CARTESIAN_POINT('',(-35.,15.,-33.));
#793=VERTEX_POINT('',#792);
#794=EDGE_CURVE('E378',#793,#783,#791,.T.);
#795=ORIENTED_EDGE('',*,*,#794,.F.);
#796=CARTESIAN_POINT('',(-35.,5.,-33.));
#797=DIRECTION('',(0.,0.,1.));
#798=DIRECTION('',(1.,0.,0.));
#799=AXIS2_PLACEMENT_3D('',#796,#797,#798);
#800=CIRCLE('',#799,10.);
#801=CARTESIAN_POINT('',(-45.,5.,-33.));
#802=VERTEX_POINT('',#801);
#803=EDGE_CURVE('E376',#802,#793,#800,.F.);
#804=ORIENTED_EDGE('',*,*,#803,.F.);
#805=DIRECTION('',(0.,1.,0.));
#806=VECTOR('',#805,1.);
#807=CARTESIAN_POINT('',(-45.,20.,-33.));
#808=LINE('',#807,#806);
#809=CARTESIAN_POINT('',(-45.,-1.,-33.));
#810=VERTEX_POINT('',#809);
#811=EDGE_CURVE('E372',#810,#802,#808,.T.);
#812=ORIENTED_EDGE('',*,*,#811,.F.);
#813=DIRECTION('',(1.,0.,0.));
#814=VECTOR('',#813,1.);
#815=CARTESIAN_POINT('',(45.,-1.,-33.));
#816=LINE('',#815,#814);
#817=CARTESIAN_POINT('',(45.,-1.,-33.));
#818=VERTEX_POINT('',#817);
#819=EDGE_CURVE('E268',#810,#818,#816,.T.);
#820=ORIENTED_EDGE('',*,*,#819,.T.);
#821=DIRECTION('',(0.,1.,0.));
#822=VECTOR('',#821,1.);
#823=CARTESIAN_POINT('',(45.,20.,-33.));
#824=LINE('',#823,#822);
#825=EDGE_CURVE('E371',#785,#818,#824,.F.);
#826=ORIENTED_EDGE('',*,*,#825,.F.);
#827=EDGE_LOOP('',(#787,#795,#804,#812,#820,#826));
#828=FACE_BOUND('',#827,.T.);
#829=ADVANCED_FACE('F772',(#828),#776,.T.);
#830=CARTESIAN_POINT('',(-48.,20.,35.));
#831=DIRECTION('',(1.,0.,0.));
#832=DIRECTION('',(0.,0.,-1.));
#833=AXIS2_PLACEMENT_3D('',#830,#831,#832);
#834=PLANE('',#833);
#835=DIRECTION('',(0.,0.,-1.));
#836=VECTOR('',#835,1.);
#837=CARTESIAN_POINT('',(-48.,5.,35.));
#838=LINE('',#837,#836);
#839=CARTESIAN_POINT('',(-48.,5.,30.));
#840=VERTEX_POINT('',#839);
#841=CARTESIAN_POINT('',(-48.,5.,-30.));
#842=VERTEX_POINT('',#841);
#843=EDGE_CURVE('E380',#840,#842,#838,.T.);
#844=ORIENTED_EDGE('',*,*,#843,.F.);
#845=DIRECTION('',(0.,1.,0.));
#846=VECTOR('',#845,1.);
#847=CARTESIAN_POINT('',(-48.,20.,30.));
#848=LINE('',#847,#846);
#849=CARTESIAN_POINT('',(-48.,-1.,30.));
#850=VERTEX_POINT('',#849);
#851=EDGE_CURVE('E374',#850,#840,#848,.T.);
#852=ORIENTED_EDGE('',*,*,#851,.F.);
#853=DIRECTION('',(0.,0.,-1.));
#854=VECTOR('',#853,1.);
#855=CARTESIAN_POINT('',(-48.,-1.,-30.));
#856=LINE('',#855,#854);
#857=CARTESIAN_POINT('',(-48.,-1.,-30.));
#858=VERTEX_POINT('',#857);
#859=EDGE_CURVE('E276',#850,#858,#856,.T.);
#860=ORIENTED_EDGE('',*,*,#859,.T.);
#861=DIRECTION('',(0.,1.,0.));
#862=VECTOR('',#861,1.);
#863=CARTESIAN_POINT('',(-48.,20.,-30.));
#864=LINE('',#863,#862);
#865=EDGE_CURVE('E381',#842,#858,#864,.F.);
#866=ORIENTED_EDGE('',*,*,#865,.F.);
#867=EDGE_LOOP('',(#844,#852,#860,#866));
#868=FACE_BOUND('',#867,.T.);
#869=ADVANCED_FACE('F774',(#868),#834,.T.);
#870=CARTESIAN_POINT('',(-50.,20.,33.));
#871=DIRECTION('',(0.,0.,-1.));
#872=DIRECTION('',(-1.,0.,0.));
#873=AXIS2_PLACEMENT_3D('',#870,#871,#872);
#874=PLANE('',#873);
#875=CARTESIAN_POINT('',(-35.,5.,33.));
#876=DIRECTION('',(0.,0.,-1.));
#877=DIRECTION('',(-1.,0.,0.));
#878=AXIS2_PLACEMENT_3D('',#875,#876,#877);
#879=CIRCLE('',#878,10.);
#880=CARTESIAN_POINT('',(-35.,15.,33.));
#881=VERTEX_POINT('',#880);
#882=CARTESIAN_POINT('',(-45.,5.,33.));
#883=VERTEX_POINT('',#882);
#884=EDGE_CURVE('E421',#881,#883,#879,.F.);
#885=ORIENTED_EDGE('',*,*,#884,.F.);
#886=DIRECTION('',(-1.,0.,0.));
#887=VECTOR('',#886,1.);
#888=CARTESIAN_POINT('',(-50.,15.,33.));
#889=LINE('',#888,#887);
#890=CARTESIAN_POINT('',(35.,15.,33.));
#891=VERTEX_POINT('',#890);
#892=EDGE_CURVE('E396',#891,#881,#889,.T.);
#893=ORIENTED_EDGE('',*,*,#892,.F.);
#894=CARTESIAN_POINT('',(35.,5.,33.));
#895=DIRECTION('',(0.,0.,-1.));
#896=DIRECTION('',(-1.,0.,0.));
#897=AXIS2_PLACEMENT_3D('',#894,#895,#896);
#898=CIRCLE('',#897,10.);
#899=CARTESIAN_POINT('',(45.,5.,33.));
#900=VERTEX_POINT('',#899);
#901=EDGE_CURVE('E418',#900,#891,#898,.F.);
#902=ORIENTED_EDGE('',*,*,#901,.F.);
#903=DIRECTION('',(0.,1.,0.));
#904=VECTOR('',#903,1.);
#905=CARTESIAN_POINT('',(45.,20.,33.));
#906=LINE('',#905,#904);
#907=CARTESIAN_POINT('',(45.,-1.,33.));
#908=VERTEX_POINT('',#907);
#909=EDGE_CURVE('E420',#908,#900,#906,.T.);
#910=ORIENTED_EDGE('',*,*,#909,.F.);
#911=DIRECTION('',(-1.,0.,0.));
#912=VECTOR('',#911,1.);
#913=CARTESIAN_POINT('',(-45.,-1.,33.));
#914=LINE('',#913,#912);
#915=CARTESIAN_POINT('',(-45.,-1.,33.));
#916=VERTEX_POINT('',#915);
#917=EDGE_CURVE('E282',#908,#916,#914,.T.);
#918=ORIENTED_EDGE('',*,*,#917,.T.);
#919=DIRECTION('',(0.,1.,0.));
#920=VECTOR('',#919,1.);
#921=CARTESIAN_POINT('',(-45.,20.,33.));
#922=LINE('',#921,#920);
#923=EDGE_CURVE('E403',#883,#916,#922,.F.);
#924=ORIENTED_EDGE('',*,*,#923,.F.);
#925=EDGE_LOOP('',(#885,#893,#902,#910,#918,#924));
#926=FACE_BOUND('',#925,.T.);
#927=ADVANCED_FACE('F593',(#926),#874,.T.);
#928=CARTESIAN_POINT('',(-35.,5.,-35.));
#929=DIRECTION('',(0.,0.,1.));
#930=DIRECTION('',(1.,0.,0.));
#931=AXIS2_PLACEMENT_3D('',#928,#929,#930);
#932=CYLINDRICAL_SURFACE('',#931,13.);
#933=ORIENTED_EDGE('',*,*,#70,.T.);
#934=CARTESIAN_POINT('',(-35.,5.,30.));
#935=DIRECTION('',(0.,0.,1.));
#936=DIRECTION('',(1.,0.,0.));
#937=AXIS2_PLACEMENT_3D('',#934,#935,#936);
#938=CIRCLE('',#937,13.);
#939=EDGE_CURVE('E383',#840,#61,#938,.F.);
#940=ORIENTED_EDGE('',*,*,#939,.F.);
#941=ORIENTED_EDGE('',*,*,#843,.T.);
#942=CARTESIAN_POINT('',(-35.,5.,-30.));
#943=DIRECTION('',(0.,0.,1.));
#944=DIRECTION('',(1.,0.,0.));
#945=AXIS2_PLACEMENT_3D('',#942,#943,#944);
#946=CIRCLE('',#945,13.);
#947=EDGE_CURVE('E394',#69,#842,#946,.T.);
#948=ORIENTED_EDGE('',*,*,#947,.F.);
#949=EDGE_LOOP('',(#933,#940,#941,#948));
#950=FACE_BOUND('',#949,.T.);
#951=ADVANCED_FACE('F595',(#950),#932,.F.);
#952=CARTESIAN_POINT('',(-45.,20.,-30.));
#953=DIRECTION('',(0.,-1.,0.));
#954=DIRECTION('',(0.,0.,-1.));
#955=AXIS2_PLACEMENT_3D('',#952,#953,#954);
#956=CYLINDRICAL_SURFACE('',#955,3.);
#957=ORIENTED_EDGE('',*,*,#865,.T.);
#958=CARTESIAN_POINT('',(-45.,-1.,-30.));
#959=DIRECTION('',(0.,-1.,0.));
#960=DIRECTION('',(0.,0.,-1.));
#961=AXIS2_PLACEMENT_3D('',#958,#959,#960);
#962=CIRCLE('',#961,3.);
#963=EDGE_CURVE('E273',#858,#810,#962,.T.);
#964=ORIENTED_EDGE('',*,*,#963,.T.);
#965=ORIENTED_EDGE('',*,*,#811,.T.);
#966=CARTESIAN_POINT('',(-45.,5.,-30.));
#967=DIRECTION('',(0.,1.,0.));
#968=DIRECTION('',(-1.,0.,0.));
#969=AXIS2_PLACEMENT_3D('',#966,#967,#968);
#970=CIRCLE('',#969,3.);
#971=EDGE_CURVE('E384',#802,#842,#970,.T.);
#972=ORIENTED_EDGE('',*,*,#971,.T.);
#973=EDGE_LOOP('',(#957,#964,#965,#972));
#974=FACE_BOUND('',#973,.T.);
#975=ADVANCED_FACE('F598',(#974),#956,.F.);
#976=CARTESIAN_POINT('',(-35.,5.,-30.));
#977=DIRECTION('',(0.,0.,1.));
#978=DIRECTION('',(1.,0.,0.));
#979=AXIS2_PLACEMENT_3D('',#976,#977,#978);
#980=TOROIDAL_SURFACE('',#979,10.,3.);
#981=ORIENTED_EDGE('',*,*,#971,.F.);
#982=ORIENTED_EDGE('',*,*,#803,.T.);
#983=CARTESIAN_POINT('',(-35.,15.,-30.));
#984=DIRECTION('',(-1.,0.,0.));
#985=DIRECTION('',(0.,0.,1.));
#986=AXIS2_PLACEMENT_3D('',#983,#984,#985);
#987=CIRCLE('',#986,3.);
#988=EDGE_CURVE('E388',#793,#69,#987,.F.);
#989=ORIENTED_EDGE('',*,*,#988,.T.);
#990=ORIENTED_EDGE('',*,*,#947,.T.);
#991=EDGE_LOOP('',(#981,#982,#989,#990));
#992=FACE_BOUND('',#991,.T.);
#993=ADVANCED_FACE('F602',(#992),#980,.F.);
#994=CARTESIAN_POINT('',(50.,15.,-30.));
#995=DIRECTION('',(-1.,0.,0.));
#996=DIRECTION('',(0.,0.,1.));
#997=AXIS2_PLACEMENT_3D('',#994,#995,#996);
#998=CYLINDRICAL_SURFACE('',#997,3.);
#999=ORIENTED_EDGE('',*,*,#988,.F.);
#1000=ORIENTED_EDGE('',*,*,#794,.T.);
#1001=CARTESIAN_POINT('',(35.,15.,-30.));
#1002=DIRECTION('',(1.,0.,0.));
#1003=DIRECTION('',(0.,1.,0.));
#1004=AXIS2_PLACEMENT_3D('',#1001,#1002,#1003);
#1005=CIRCLE('',#1004,3.);
#1006=EDGE_CURVE('E406',#783,#53,#1005,.T.);
#1007=ORIENTED_EDGE('',*,*,#1006,.T.);
#1008=ORIENTED_EDGE('',*,*,#76,.T.);
#1009=EDGE_LOOP('',(#999,#1000,#1007,#1008));
#1010=FACE_BOUND('',#1009,.T.);
#1011=ADVANCED_FACE('F606',(#1010),#998,.F.);
#1012=CARTESIAN_POINT('',(35.,5.,-30.));
#1013=DIRECTION('',(0.,0.,1.));
#1014=DIRECTION('',(1.,0.,0.));
#1015=AXIS2_PLACEMENT_3D('',#1012,#1013,#1014);
#1016=TOROIDAL_SURFACE('',#1015,10.,3.);
#1017=ORIENTED_EDGE('',*,*,#1006,.F.);
#1018=ORIENTED_EDGE('',*,*,#786,.T.);
#1019=CARTESIAN_POINT('',(45.,5.,-30.));
#1020=DIRECTION('',(0.,-1.,0.));
#1021=DIRECTION('',(0.,0.,-1.));
#1022=AXIS2_PLACEMENT_3D('',#1019,#1020,#1021);
#1023=CIRCLE('',#1022,3.);
#1024=EDGE_CURVE('E408',#785,#694,#1023,.T.);
#1025=ORIENTED_EDGE('',*,*,#1024,.T.);
#1026=ORIENTED_EDGE('',*,*,#695,.T.);
#1027=EDGE_LOOP('',(#1017,#1018,#1025,#1026));
#1028=FACE_BOUND('',#1027,.T.);
#1029=ADVANCED_FACE('F610',(#1028),#1016,.F.);
#1030=CARTESIAN_POINT('',(45.,20.,-30.));
#1031=DIRECTION('',(0.,-1.,0.));
#1032=DIRECTION('',(0.,0.,-1.));
#1033=AXIS2_PLACEMENT_3D('',#1030,#1031,#1032);
#1034=CYLINDRICAL_SURFACE('',#1033,3.);
#1035=ORIENTED_EDGE('',*,*,#1024,.F.);
#1036=ORIENTED_EDGE('',*,*,#825,.T.);
#1037=CARTESIAN_POINT('',(45.,-1.,-30.));
#1038=DIRECTION('',(0.,-1.,0.));
#1039=DIRECTION('',(0.,0.,-1.));
#1040=AXIS2_PLACEMENT_3D('',#1037,#1038,#1039);
#1041=CIRCLE('',#1040,3.);
#1042=EDGE_CURVE('E266',#818,#751,#1041,.T.);
#1043=ORIENTED_EDGE('',*,*,#1042,.T.);
#1044=ORIENTED_EDGE('',*,*,#752,.T.);
#1045=EDGE_LOOP('',(#1035,#1036,#1043,#1044));
#1046=FACE_BOUND('',#1045,.T.);
#1047=ADVANCED_FACE('F614',(#1046),#1034,.F.);
#1048=CARTESIAN_POINT('',(45.,20.,30.));
#1049=DIRECTION('',(0.,-1.,0.));
#1050=DIRECTION('',(0.,0.,-1.));
#1051=AXIS2_PLACEMENT_3D('',#1048,#1049,#1050);
#1052=CYLINDRICAL_SURFACE('',#1051,3.);
#1053=ORIENTED_EDGE('',*,*,#733,.T.);
#1054=CARTESIAN_POINT('',(45.,-1.,30.));
#1055=DIRECTION('',(0.,-1.,0.));
#1056=DIRECTION('',(0.,0.,-1.));
#1057=AXIS2_PLACEMENT_3D('',#1054,#1055,#1056);
#1058=CIRCLE('',#1057,3.);
#1059=EDGE_CURVE('E285',#726,#908,#1058,.T.);
#1060=ORIENTED_EDGE('',*,*,#1059,.T.);
#1061=ORIENTED_EDGE('',*,*,#909,.T.);
#1062=CARTESIAN_POINT('',(45.,5.,30.));
#1063=DIRECTION('',(0.,1.,0.));
#1064=DIRECTION('',(-1.,0.,0.));
#1065=AXIS2_PLACEMENT_3D('',#1062,#1063,#1064);
#1066=CIRCLE('',#1065,3.);
#1067=EDGE_CURVE('E411',#900,#645,#1066,.T.);
#1068=ORIENTED_EDGE('',*,*,#1067,.T.);
#1069=EDGE_LOOP('',(#1053,#1060,#1061,#1068));
#1070=FACE_BOUND('',#1069,.T.);
#1071=ADVANCED_FACE('F618',(#1070),#1052,.F.);
#1072=CARTESIAN_POINT('',(35.,5.,30.));
#1073=DIRECTION('',(0.,0.,-1.));
#1074=DIRECTION('',(-1.,0.,0.));
#1075=AXIS2_PLACEMENT_3D('',#1072,#1073,#1074);
#1076=TOROIDAL_SURFACE('',#1075,10.,3.);
#1077=ORIENTED_EDGE('',*,*,#1067,.F.);
#1078=ORIENTED_EDGE('',*,*,#901,.T.);
#1079=CARTESIAN_POINT('',(35.,15.,30.));
#1080=DIRECTION('',(1.,0.,0.));
#1081=DIRECTION('',(0.,0.,-1.));
#1082=AXIS2_PLACEMENT_3D('',#1079,#1080,#1081);
#1083=CIRCLE('',#1082,3.);
#1084=EDGE_CURVE('E414',#891,#51,#1083,.F.);
#1085=ORIENTED_EDGE('',*,*,#1084,.T.);
#1086=ORIENTED_EDGE('',*,*,#653,.T.);
#1087=EDGE_LOOP('',(#1077,#1078,#1085,#1086));
#1088=FACE_BOUND('',#1087,.T.);
#1089=ADVANCED_FACE('F622',(#1088),#1076,.F.);
#1090=CARTESIAN_POINT('',(50.,15.,30.));
#1091=DIRECTION('',(1.,0.,0.));
#1092=DIRECTION('',(0.,0.,-1.));
#1093=AXIS2_PLACEMENT_3D('',#1090,#1091,#1092);
#1094=CYLINDRICAL_SURFACE('',#1093,3.);
#1095=ORIENTED_EDGE('',*,*,#1084,.F.);
#1096=ORIENTED_EDGE('',*,*,#892,.T.);
#1097=CARTESIAN_POINT('',(-35.,15.,30.));
#1098=DIRECTION('',(-1.,0.,0.));
#1099=DIRECTION('',(0.,-1.,0.));
#1100=AXIS2_PLACEMENT_3D('',#1097,#1098,#1099);
#1101=CIRCLE('',#1100,3.);
#1102=EDGE_CURVE('E417',#881,#61,#1101,.T.);
#1103=ORIENTED_EDGE('',*,*,#1102,.T.);
#1104=ORIENTED_EDGE('',*,*,#62,.T.);
#1105=EDGE_LOOP('',(#1095,#1096,#1103,#1104));
#1106=FACE_BOUND('',#1105,.T.);
#1107=ADVANCED_FACE('F626',(#1106),#1094,.F.);
#1108=CARTESIAN_POINT('',(-35.,5.,30.));
#1109=DIRECTION('',(0.,0.,-1.));
#1110=DIRECTION('',(-1.,0.,0.));
#1111=AXIS2_PLACEMENT_3D('',#1108,#1109,#1110);
#1112=TOROIDAL_SURFACE('',#1111,10.,3.);
#1113=ORIENTED_EDGE('',*,*,#1102,.F.);
#1114=ORIENTED_EDGE('',*,*,#884,.T.);
#1115=CARTESIAN_POINT('',(-45.,5.,30.));
#1116=DIRECTION('',(0.,-1.,0.));
#1117=DIRECTION('',(0.,0.,-1.));
#1118=AXIS2_PLACEMENT_3D('',#1115,#1116,#1117);
#1119=CIRCLE('',#1118,3.);
#1120=EDGE_CURVE('E352',#883,#840,#1119,.T.);
#1121=ORIENTED_EDGE('',*,*,#1120,.T.);
#1122=ORIENTED_EDGE('',*,*,#939,.T.);
#1123=EDGE_LOOP('',(#1113,#1114,#1121,#1122));
#1124=FACE_BOUND('',#1123,.T.);
#1125=ADVANCED_FACE('F578',(#1124),#1112,.F.);
#1126=CARTESIAN_POINT('',(-45.,20.,30.));
#1127=DIRECTION('',(0.,-1.,0.));
#1128=DIRECTION('',(0.,0.,-1.));
#1129=AXIS2_PLACEMENT_3D('',#1126,#1127,#1128);
#1130=CYLINDRICAL_SURFACE('',#1129,3.);
#1131=ORIENTED_EDGE('',*,*,#1120,.F.);
#1132=ORIENTED_EDGE('',*,*,#923,.T.);
#1133=CARTESIAN_POINT('',(-45.,-1.,30.));
#1134=DIRECTION('',(0.,-1.,0.));
#1135=DIRECTION('',(0.,0.,-1.));
#1136=AXIS2_PLACEMENT_3D('',#1133,#1134,#1135);
#1137=CIRCLE('',#1136,3.);
#1138=EDGE_CURVE('E279',#916,#850,#1137,.T.);
#1139=ORIENTED_EDGE('',*,*,#1138,.T.);
#1140=ORIENTED_EDGE('',*,*,#851,.T.);
#1141=EDGE_LOOP('',(#1131,#1132,#1139,#1140));
#1142=FACE_BOUND('',#1141,.T.);
#1143=ADVANCED_FACE('F572',(#1142),#1130,.F.);
#1144=CARTESIAN_POINT('',(9.99999999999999,5.,0.));
#1145=DIRECTION('',(0.,1.,0.));
#1146=DIRECTION('',(0.,0.,1.));
#1147=AXIS2_PLACEMENT_3D('',#1144,#1145,#1146);
#1148=PLANE('',#1147);
#1149=CARTESIAN_POINT('',(9.99999999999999,5.,0.));
#1150=DIRECTION('',(0.,1.,0.));
#1151=DIRECTION('',(0.,0.,1.));
#1152=AXIS2_PLACEMENT_3D('',#1149,#1150,#1151);
#1153=CIRCLE('',#1152,1.95);
#1154=CARTESIAN_POINT('',(9.99999999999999,5.,1.95));
#1155=VERTEX_POINT('',#1154);
#1156=EDGE_CURVE('E338',#1155,#1155,#1153,.T.);
#1157=ORIENTED_EDGE('',*,*,#1156,.T.);
#1158=EDGE_LOOP('',(#1157));
#1159=FACE_BOUND('',#1158,.T.);
#1160=CARTESIAN_POINT('',(9.99999999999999,5.,0.));
#1161=DIRECTION('',(0.,1.,0.));
#1162=DIRECTION('',(0.,0.,1.));
#1163=AXIS2_PLACEMENT_3D('',#1160,#1161,#1162);
#1164=CIRCLE('',#1163,3.);
#1165=CARTESIAN_POINT('',(9.99999999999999,5.,3.));
#1166=VERTEX_POINT('',#1165);
#1167=EDGE_CURVE('E349',#1166,#1166,#1164,.T.);
#1168=ORIENTED_EDGE('',*,*,#1167,.F.);
#1169=EDGE_LOOP('',(#1168));
#1170=FACE_BOUND('',#1169,.T.);
#1171=ADVANCED_FACE('F567',(#1159,#1170),#1148,.F.);
#1172=CARTESIAN_POINT('',(9.99999999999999,5.,0.));
#1173=DIRECTION('',(0.,1.,0.));
#1174=DIRECTION('',(0.,0.,1.));
#1175=AXIS2_PLACEMENT_3D('',#1172,#1173,#1174);
#1176=CONICAL_SURFACE('',#1175,3.,0.0872664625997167);
#1177=CARTESIAN_POINT('',(9.99999999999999,17.0871557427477,0.));
#1178=DIRECTION('',(0.,-1.,0.));
#1179=DIRECTION('',(0.,0.,-1.));
#1180=AXIS2_PLACEMENT_3D('',#1177,#1178,#1179);
#1181=CIRCLE('',#1180,4.05748910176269);
#1182=CARTESIAN_POINT('',(9.99999999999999,17.0871557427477,-4.05748910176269));
#1183=VERTEX_POINT('',#1182);
#1184=EDGE_CURVE('E521',#1183,#1183,#1181,.T.);
#1185=ORIENTED_EDGE('',*,*,#1184,.T.);
#1186=EDGE_LOOP('',(#1185));
#1187=FACE_BOUND('',#1186,.T.);
#1188=ORIENTED_EDGE('',*,*,#1167,.T.);
#1189=EDGE_LOOP('',(#1188));
#1190=FACE_BOUND('',#1189,.T.);
#1191=ADVANCED_FACE('F563',(#1187,#1190),#1176,.T.);
#1192=CARTESIAN_POINT('',(-25.,5.,0.));
#1193=DIRECTION('',(0.,1.,0.));
#1194=DIRECTION('',(0.,0.,1.));
#1195=AXIS2_PLACEMENT_3D('',#1192,#1193,#1194);
#1196=PLANE('',#1195);
#1197=CARTESIAN_POINT('',(-25.,5.,0.));
#1198=DIRECTION('',(0.,1.,0.));
#1199=DIRECTION('',(0.,0.,1.));
#1200=AXIS2_PLACEMENT_3D('',#1197,#1198,#1199);
#1201=CIRCLE('',#1200,1.95);
#1202=CARTESIAN_POINT('',(-25.,5.,1.95));
#1203=VERTEX_POINT('',#1202);
#1204=EDGE_CURVE('E345',#1203,#1203,#1201,.T.);
#1205=ORIENTED_EDGE('',*,*,#1204,.T.);
#1206=EDGE_LOOP('',(#1205));
#1207=FACE_BOUND('',#1206,.T.);
#1208=CARTESIAN_POINT('',(-25.,5.,0.));
#1209=DIRECTION('',(0.,1.,0.));
#1210=DIRECTION('',(0.,0.,1.));
#1211=AXIS2_PLACEMENT_3D('',#1208,#1209,#1210);
#1212=CIRCLE('',#1211,3.);
#1213=CARTESIAN_POINT('',(-25.,5.,3.));
#1214=VERTEX_POINT('',#1213);
#1215=EDGE_CURVE('E346',#1214,#1214,#1212,.T.);
#1216=ORIENTED_EDGE('',*,*,#1215,.F.);
#1217=EDGE_LOOP('',(#1216));
#1218=FACE_BOUND('',#1217,.T.);
#1219=ADVANCED_FACE('F566',(#1207,#1218),#1196,.F.);
#1220=CARTESIAN_POINT('',(-25.,5.,0.));
#1221=DIRECTION('',(0.,1.,0.));
#1222=DIRECTION('',(0.,0.,1.));
#1223=AXIS2_PLACEMENT_3D('',#1220,#1221,#1222);
#1224=CONICAL_SURFACE('',#1223,3.,0.0872664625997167);
#1225=CARTESIAN_POINT('',(-25.,17.0871557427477,0.));
#1226=DIRECTION('',(0.,-1.,0.));
#1227=DIRECTION('',(0.,0.,-1.));
#1228=AXIS2_PLACEMENT_3D('',#1225,#1226,#1227);
#1229=CIRCLE('',#1228,4.05748910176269);
#1230=CARTESIAN_POINT('',(-25.,17.0871557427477,-4.05748910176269));
#1231=VERTEX_POINT('',#1230);
#1232=EDGE_CURVE('E11',#1231,#1231,#1229,.T.);
#1233=ORIENTED_EDGE('',*,*,#1232,.T.);
#1234=EDGE_LOOP('',(#1233));
#1235=FACE_BOUND('',#1234,.T.);
#1236=ORIENTED_EDGE('',*,*,#1215,.T.);
#1237=EDGE_LOOP('',(#1236));
#1238=FACE_BOUND('',#1237,.T.);
#1239=ADVANCED_FACE('F852',(#1235,#1238),#1224,.T.);
#1240=CARTESIAN_POINT('',(-25.,20.,0.));
#1241=DIRECTION('',(0.,1.,0.));
#1242=DIRECTION('',(0.,0.,1.));
#1243=AXIS2_PLACEMENT_3D('',#1240,#1241,#1242);
#1244=CYLINDRICAL_SURFACE('',#1243,1.95);
#1245=CARTESIAN_POINT('',(-25.,17.85,0.));
#1246=DIRECTION('',(0.,1.,0.));
#1247=DIRECTION('',(0.,0.,1.));
#1248=AXIS2_PLACEMENT_3D('',#1245,#1246,#1247);
#1249=CIRCLE('',#1248,1.95);
#1250=CARTESIAN_POINT('',(-25.,17.85,1.95));
#1251=VERTEX_POINT('',#1250);
#1252=EDGE_CURVE('E342',#1251,#1251,#1249,.T.);
#1253=ORIENTED_EDGE('',*,*,#1252,.T.);
#1254=EDGE_LOOP('',(#1253));
#1255=FACE_BOUND('',#1254,.T.);
#1256=ORIENTED_EDGE('',*,*,#1204,.F.);
#1257=EDGE_LOOP('',(#1256));
#1258=FACE_BOUND('',#1257,.T.);
#1259=ADVANCED_FACE('F848',(#1255,#1258),#1244,.F.);
#1260=CARTESIAN_POINT('',(-25.,20.,0.));
#1261=DIRECTION('',(0.,1.,0.));
#1262=DIRECTION('',(0.,0.,1.));
#1263=AXIS2_PLACEMENT_3D('',#1260,#1261,#1262);
#1264=CONICAL_SURFACE('',#1263,4.1,0.785398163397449);
#1265=ORIENTED_EDGE('',*,*,#1252,.F.);
#1266=EDGE_LOOP('',(#1265));
#1267=FACE_BOUND('',#1266,.T.);
#1268=ORIENTED_EDGE('',*,*,#260,.T.);
#1269=EDGE_LOOP('',(#1268));
#1270=FACE_BOUND('',#1269,.T.);
#1271=ADVANCED_FACE('F844',(#1267,#1270),#1264,.F.);
#1272=CARTESIAN_POINT('',(9.99999999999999,20.,0.));
#1273=DIRECTION('',(0.,1.,0.));
#1274=DIRECTION('',(0.,0.,1.));
#1275=AXIS2_PLACEMENT_3D('',#1272,#1273,#1274);
#1276=CYLINDRICAL_SURFACE('',#1275,1.95);
#1277=CARTESIAN_POINT('',(9.99999999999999,17.85,0.));
#1278=DIRECTION('',(0.,1.,0.));
#1279=DIRECTION('',(0.,0.,1.));
#1280=AXIS2_PLACEMENT_3D('',#1277,#1278,#1279);
#1281=CIRCLE('',#1280,1.95);
#1282=CARTESIAN_POINT('',(9.99999999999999,17.85,1.95));
#1283=VERTEX_POINT('',#1282);
#1284=EDGE_CURVE('E335',#1283,#1283,#1281,.T.);
#1285=ORIENTED_EDGE('',*,*,#1284,.T.);
#1286=EDGE_LOOP('',(#1285));
#1287=FACE_BOUND('',#1286,.T.);
#1288=ORIENTED_EDGE('',*,*,#1156,.F.);
#1289=EDGE_LOOP('',(#1288));
#1290=FACE_BOUND('',#1289,.T.);
#1291=ADVANCED_FACE('F840',(#1287,#1290),#1276,.F.);
#1292=CARTESIAN_POINT('',(9.99999999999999,20.,0.));
#1293=DIRECTION('',(0.,1.,0.));
#1294=DIRECTION('',(0.,0.,1.));
#1295=AXIS2_PLACEMENT_3D('',#1292,#1293,#1294);
#1296=CONICAL_SURFACE('',#1295,4.1,0.785398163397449);
#1297=ORIENTED_EDGE('',*,*,#1284,.F.);
#1298=EDGE_LOOP('',(#1297));
#1299=FACE_BOUND('',#1298,.T.);
#1300=ORIENTED_EDGE('',*,*,#249,.T.);
#1301=EDGE_LOOP('',(#1300));
#1302=FACE_BOUND('',#1301,.T.);
#1303=ADVANCED_FACE('F560',(#1299,#1302),#1296,.F.);
#1304=CARTESIAN_POINT('',(9.99999999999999,17.,0.));
#1305=DIRECTION('',(0.,-1.,0.));
#1306=DIRECTION('',(0.,0.,-1.));
#1307=AXIS2_PLACEMENT_3D('',#1304,#1305,#1306);
#1308=TOROIDAL_SURFACE('',#1307,5.05368379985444,1.);
#1309=ORIENTED_EDGE('',*,*,#31,.F.);
#1310=EDGE_LOOP('',(#1309));
#1311=FACE_BOUND('',#1310,.T.);
#1312=ORIENTED_EDGE('',*,*,#1184,.F.);
#1313=EDGE_LOOP('',(#1312));
#1314=FACE_BOUND('',#1313,.T.);
#1315=ADVANCED_FACE('F557',(#1311,#1314),#1308,.F.);
#1316=CARTESIAN_POINT('',(-25.,17.,0.));
#1317=DIRECTION('',(0.,-1.,0.));
#1318=DIRECTION('',(0.,0.,-1.));
#1319=AXIS2_PLACEMENT_3D('',#1316,#1317,#1318);
#1320=TOROIDAL_SURFACE('',#1319,5.05368379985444,1.);
#1321=ORIENTED_EDGE('',*,*,#42,.F.);
#1322=EDGE_LOOP('',(#1321));
#1323=FACE_BOUND('',#1322,.T.);
#1324=ORIENTED_EDGE('',*,*,#1232,.F.);
#1325=EDGE_LOOP('',(#1324));
#1326=FACE_BOUND('',#1325,.T.);
#1327=ADVANCED_FACE('F36',(#1323,#1326),#1320,.F.);
#1328=CARTESIAN_POINT('',(45.,-1.,-30.));
#1329=DIRECTION('',(0.,1.,0.));
#1330=DIRECTION('',(0.,0.,1.));
#1331=AXIS2_PLACEMENT_3D('',#1328,#1329,#1330);
#1332=CYLINDRICAL_SURFACE('',#1331,4.);
#1333=ORIENTED_EDGE('',*,*,#313,.T.);
#1334=ORIENTED_EDGE('',*,*,#766,.F.);
#1335=CARTESIAN_POINT('',(45.,-1.,-30.));
#1336=DIRECTION('',(0.,-1.,0.));
#1337=DIRECTION('',(1.,0.,0.));
#1338=AXIS2_PLACEMENT_3D('',#1335,#1336,#1337);
#1339=CIRCLE('',#1338,4.);
#1340=CARTESIAN_POINT('',(45.,-1.,-34.));
#1341=VERTEX_POINT('',#1340);
#1342=EDGE_CURVE('E243',#1341,#759,#1339,.T.);
#1343=ORIENTED_EDGE('',*,*,#1342,.F.);
#1344=DIRECTION('',(0.,1.,0.));
#1345=VECTOR('',#1344,1.);
#1346=CARTESIAN_POINT('',(45.,-1.,-34.));
#1347=LINE('',#1346,#1345);
#1348=EDGE_CURVE('E301',#1341,#310,#1347,.T.);
#1349=ORIENTED_EDGE('',*,*,#1348,.T.);
#1350=EDGE_LOOP('',(#1333,#1334,#1343,#1349));
#1351=FACE_BOUND('',#1350,.T.);
#1352=ADVANCED_FACE('F258',(#1351),#1332,.T.);
#1353=CARTESIAN_POINT('',(45.,-1.,30.));
#1354=DIRECTION('',(0.,1.,0.));
#1355=DIRECTION('',(0.,0.,1.));
#1356=AXIS2_PLACEMENT_3D('',#1353,#1354,#1355);
#1357=CYLINDRICAL_SURFACE('',#1356,4.);
#1358=ORIENTED_EDGE('',*,*,#364,.T.);
#1359=DIRECTION('',(0.,1.,0.));
#1360=VECTOR('',#1359,1.);
#1361=CARTESIAN_POINT('',(45.,-1.,34.));
#1362=LINE('',#1361,#1360);
#1363=CARTESIAN_POINT('',(45.,-1.,34.));
#1364=VERTEX_POINT('',#1363);
#1365=EDGE_CURVE('E330',#1364,#354,#1362,.T.);
#1366=ORIENTED_EDGE('',*,*,#1365,.F.);
#1367=CARTESIAN_POINT('',(45.,-1.,30.));
#1368=DIRECTION('',(0.,-1.,0.));
#1369=DIRECTION('',(1.,0.,0.));
#1370=AXIS2_PLACEMENT_3D('',#1367,#1368,#1369);
#1371=CIRCLE('',#1370,4.);
#1372=EDGE_CURVE('E291',#718,#1364,#1371,.T.);
#1373=ORIENTED_EDGE('',*,*,#1372,.F.);
#1374=ORIENTED_EDGE('',*,*,#719,.T.);
#1375=EDGE_LOOP('',(#1358,#1366,#1373,#1374));
#1376=FACE_BOUND('',#1375,.T.);
#1377=ADVANCED_FACE('F802',(#1376),#1357,.T.);
#1378=CARTESIAN_POINT('',(-45.,-1.,34.));
#1379=DIRECTION('',(0.,0.,-1.));
#1380=DIRECTION('',(-1.,0.,0.));
#1381=AXIS2_PLACEMENT_3D('',#1378,#1379,#1380);
#1382=PLANE('',#1381);
#1383=ORIENTED_EDGE('',*,*,#355,.T.);
#1384=DIRECTION('',(0.,1.,0.));
#1385=VECTOR('',#1384,1.);
#1386=CARTESIAN_POINT('',(-45.,-1.,34.));
#1387=LINE('',#1386,#1385);
#1388=CARTESIAN_POINT('',(-45.,-1.,34.));
#1389=VERTEX_POINT('',#1388);
#1390=EDGE_CURVE('E327',#1389,#346,#1387,.T.);
#1391=ORIENTED_EDGE('',*,*,#1390,.F.);
#1392=DIRECTION('',(1.,0.,0.));
#1393=VECTOR('',#1392,1.);
#1394=CARTESIAN_POINT('',(-45.,-1.,34.));
#1395=LINE('',#1394,#1393);
#1396=EDGE_CURVE('E293',#1364,#1389,#1395,.F.);
#1397=ORIENTED_EDGE('',*,*,#1396,.F.);
#1398=ORIENTED_EDGE('',*,*,#1365,.T.);
#1399=EDGE_LOOP('',(#1383,#1391,#1397,#1398));
#1400=FACE_BOUND('',#1399,.T.);
#1401=ADVANCED_FACE('F804',(#1400),#1382,.F.);
#1402=CARTESIAN_POINT('',(-45.,-1.,30.));
#1403=DIRECTION('',(0.,1.,0.));
#1404=DIRECTION('',(0.,0.,1.));
#1405=AXIS2_PLACEMENT_3D('',#1402,#1403,#1404);
#1406=CYLINDRICAL_SURFACE('',#1405,4.);
#1407=ORIENTED_EDGE('',*,*,#347,.T.);
#1408=DIRECTION('',(0.,1.,0.));
#1409=VECTOR('',#1408,1.);
#1410=CARTESIAN_POINT('',(-49.,-1.,30.));
#1411=LINE('',#1410,#1409);
#1412=CARTESIAN_POINT('',(-49.,-1.,30.));
#1413=VERTEX_POINT('',#1412);
#1414=EDGE_CURVE('E324',#1413,#337,#1411,.T.);
#1415=ORIENTED_EDGE('',*,*,#1414,.F.);
#1416=CARTESIAN_POINT('',(-45.,-1.,30.));
#1417=DIRECTION('',(0.,-1.,0.));
#1418=DIRECTION('',(1.,0.,0.));
#1419=AXIS2_PLACEMENT_3D('',#1416,#1417,#1418);
#1420=CIRCLE('',#1419,4.);
#1421=EDGE_CURVE('E295',#1389,#1413,#1420,.T.);
#1422=ORIENTED_EDGE('',*,*,#1421,.F.);
#1423=ORIENTED_EDGE('',*,*,#1390,.T.);
#1424=EDGE_LOOP('',(#1407,#1415,#1422,#1423));
#1425=FACE_BOUND('',#1424,.T.);
#1426=ADVANCED_FACE('F808',(#1425),#1406,.T.);
#1427=CARTESIAN_POINT('',(-49.,-1.,-30.));
#1428=DIRECTION('',(1.,0.,0.));
#1429=DIRECTION('',(0.,0.,-1.));
#1430=AXIS2_PLACEMENT_3D('',#1427,#1428,#1429);
#1431=PLANE('',#1430);
#1432=ORIENTED_EDGE('',*,*,#338,.T.);
#1433=DIRECTION('',(0.,1.,0.));
#1434=VECTOR('',#1433,1.);
#1435=CARTESIAN_POINT('',(-49.,-1.,-30.));
#1436=LINE('',#1435,#1434);
#1437=CARTESIAN_POINT('',(-49.,-1.,-30.));
#1438=VERTEX_POINT('',#1437);
#1439=EDGE_CURVE('E321',#1438,#329,#1436,.T.);
#1440=ORIENTED_EDGE('',*,*,#1439,.F.);
#1441=DIRECTION('',(0.,0.,1.));
#1442=VECTOR('',#1441,1.);
#1443=CARTESIAN_POINT('',(-49.,-1.,-30.));
#1444=LINE('',#1443,#1442);
#1445=EDGE_CURVE('E297',#1413,#1438,#1444,.F.);
#1446=ORIENTED_EDGE('',*,*,#1445,.F.);
#1447=ORIENTED_EDGE('',*,*,#1414,.T.);
#1448=EDGE_LOOP('',(#1432,#1440,#1446,#1447));
#1449=FACE_BOUND('',#1448,.T.);
#1450=ADVANCED_FACE('F814',(#1449),#1431,.F.);
#1451=CARTESIAN_POINT('',(-45.,-1.,-30.));
#1452=DIRECTION('',(0.,1.,0.));
#1453=DIRECTION('',(0.,0.,1.));
#1454=AXIS2_PLACEMENT_3D('',#1451,#1452,#1453);
#1455=CYLINDRICAL_SURFACE('',#1454,4.);
#1456=ORIENTED_EDGE('',*,*,#330,.T.);
#1457=DIRECTION('',(0.,1.,0.));
#1458=VECTOR('',#1457,1.);
#1459=CARTESIAN_POINT('',(-45.,-1.,-34.));
#1460=LINE('',#1459,#1458);
#1461=CARTESIAN_POINT('',(-45.,-1.,-34.));
#1462=VERTEX_POINT('',#1461);
#1463=EDGE_CURVE('E318',#1462,#320,#1460,.T.);
#1464=ORIENTED_EDGE('',*,*,#1463,.F.);
#1465=CARTESIAN_POINT('',(-45.,-1.,-30.));
#1466=DIRECTION('',(0.,-1.,0.));
#1467=DIRECTION('',(1.,0.,0.));
#1468=AXIS2_PLACEMENT_3D('',#1465,#1466,#1467);
#1469=CIRCLE('',#1468,4.);
#1470=EDGE_CURVE('E299',#1438,#1462,#1469,.T.);
#1471=ORIENTED_EDGE('',*,*,#1470,.F.);
#1472=ORIENTED_EDGE('',*,*,#1439,.T.);
#1473=EDGE_LOOP('',(#1456,#1464,#1471,#1472));
#1474=FACE_BOUND('',#1473,.T.);
#1475=ADVANCED_FACE('F816',(#1474),#1455,.T.);
#1476=CARTESIAN_POINT('',(45.,-1.,-34.));
#1477=DIRECTION('',(0.,0.,1.));
#1478=DIRECTION('',(1.,0.,0.));
#1479=AXIS2_PLACEMENT_3D('',#1476,#1477,#1478);
#1480=PLANE('',#1479);
#1481=ORIENTED_EDGE('',*,*,#321,.T.);
#1482=ORIENTED_EDGE('',*,*,#1348,.F.);
#1483=DIRECTION('',(1.,0.,0.));
#1484=VECTOR('',#1483,1.);
#1485=CARTESIAN_POINT('',(45.,-1.,-34.));
#1486=LINE('',#1485,#1484);
#1487=EDGE_CURVE('E251',#1462,#1341,#1486,.T.);
#1488=ORIENTED_EDGE('',*,*,#1487,.F.);
#1489=ORIENTED_EDGE('',*,*,#1463,.T.);
#1490=EDGE_LOOP('',(#1481,#1482,#1488,#1489));
#1491=FACE_BOUND('',#1490,.T.);
#1492=ADVANCED_FACE('F818',(#1491),#1480,.F.);
#1493=CARTESIAN_POINT('',(45.,-1.,-30.));
#1494=DIRECTION('',(0.,-1.,0.));
#1495=DIRECTION('',(1.,0.,0.));
#1496=AXIS2_PLACEMENT_3D('',#1493,#1494,#1495);
#1497=PLANE('',#1496);
#1498=ORIENTED_EDGE('',*,*,#1342,.T.);
#1499=ORIENTED_EDGE('',*,*,#760,.F.);
#1500=ORIENTED_EDGE('',*,*,#1042,.F.);
#1501=ORIENTED_EDGE('',*,*,#819,.F.);
#1502=ORIENTED_EDGE('',*,*,#963,.F.);
#1503=ORIENTED_EDGE('',*,*,#859,.F.);
#1504=ORIENTED_EDGE('',*,*,#1138,.F.);
#1505=ORIENTED_EDGE('',*,*,#917,.F.);
#1506=ORIENTED_EDGE('',*,*,#1059,.F.);
#1507=ORIENTED_EDGE('',*,*,#727,.F.);
#1508=ORIENTED_EDGE('',*,*,#1372,.T.);
#1509=ORIENTED_EDGE('',*,*,#1396,.T.);
#1510=ORIENTED_EDGE('',*,*,#1421,.T.);
#1511=ORIENTED_EDGE('',*,*,#1445,.T.);
#1512=ORIENTED_EDGE('',*,*,#1470,.T.);
#1513=ORIENTED_EDGE('',*,*,#1487,.T.);
#1514=EDGE_LOOP('',(#1498,#1499,#1500,#1501,#1502,#1503,#1504,#1505,#1506,#1507,#1508,#1509,
#1510,#1511,#1512,#1513));
#1515=FACE_BOUND('',#1514,.T.);
#1516=ADVANCED_FACE('F245',(#1515),#1497,.T.);
#1517=CLOSED_SHELL('',(#80,#138,#178,#236,#298,#415,#439,#457,#475,#493,#519,#536,#561,#585,
#603,#621,#633,#663,#680,#705,#738,#771,#829,#869,#927,#951,#975,#993,#1011,#1029,#1047,#1071,
#1089,#1107,#1125,#1143,#1171,#1191,#1219,#1239,#1259,#1271,#1291,#1303,#1315,#1327,#1352,#1377,
#1401,#1426,#1450,#1475,#1492,#1516));
#1518=MANIFOLD_SOLID_BREP('B2',#1517);
#1519=ADVANCED_BREP_SHAPE_REPRESENTATION('',(#18,#1518),#14);
#1520=SHAPE_DEFINITION_REPRESENTATION(#9,#1519);
ENDSEC;
END-ISO-10303-21;
